VERSION 5.7 ;
  NOWIREEXTENSIONATPIN ON ;
  DIVIDERCHAR "/" ;
  BUSBITCHARS "[]" ;
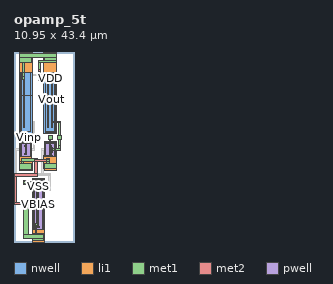
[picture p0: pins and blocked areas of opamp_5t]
MACRO opamp_5t
  CLASS BLOCK ;
  FOREIGN opamp_5t ;
  ORIGIN -1.350 23.320 ;
  SIZE 10.950 BY 43.400 ;
  PIN VDD
    USE POWER ;
    ANTENNADIFFAREA 24.823999 ;
    PORT
      LAYER nwell ;
        RECT 2.510 10.240 5.590 15.940 ;
        RECT 2.500 1.470 5.590 10.240 ;
        RECT 2.500 1.240 5.580 1.470 ;
        RECT 8.060 1.410 11.140 15.880 ;
      LAYER li1 ;
        RECT 2.510 15.470 5.620 20.080 ;
        RECT 2.900 15.380 5.200 15.470 ;
        RECT 8.060 15.400 11.170 20.010 ;
        RECT 2.900 2.030 3.070 15.380 ;
        RECT 3.570 2.935 3.740 14.475 ;
        RECT 5.030 2.030 5.200 15.380 ;
        RECT 2.900 1.860 5.200 2.030 ;
        RECT 8.450 15.320 10.750 15.400 ;
        RECT 8.450 1.970 8.620 15.320 ;
        RECT 9.120 2.875 9.290 14.415 ;
        RECT 10.580 1.970 10.750 15.320 ;
        RECT 8.450 1.800 10.750 1.970 ;
      LAYER met1 ;
        RECT 3.390 19.730 10.720 19.760 ;
        RECT 2.630 19.720 10.720 19.730 ;
        RECT 2.630 18.760 10.980 19.720 ;
        RECT 2.630 17.630 5.390 18.760 ;
        RECT 8.220 18.060 10.980 18.760 ;
        RECT 6.910 17.635 10.980 18.060 ;
        RECT 3.340 14.455 3.650 17.630 ;
        RECT 6.910 15.690 7.335 17.635 ;
        RECT 8.220 17.620 10.980 17.635 ;
        RECT 3.340 13.790 3.770 14.455 ;
        RECT 3.540 2.955 3.770 13.790 ;
        RECT 6.900 14.100 7.340 14.130 ;
        RECT 9.090 14.100 9.320 14.395 ;
        RECT 6.900 13.660 9.320 14.100 ;
        RECT 6.900 13.630 7.340 13.660 ;
        RECT 9.090 2.895 9.320 13.660 ;
      LAYER met2 ;
        RECT 6.910 16.145 7.335 16.170 ;
        RECT 6.880 15.720 7.365 16.145 ;
        RECT 6.910 14.100 7.335 15.720 ;
        RECT 6.870 13.660 7.370 14.100 ;
    END
  END VDD
  PIN Vout
    ANTENNADIFFAREA 3.668500 ;
    PORT
      LAYER li1 ;
        RECT 9.910 2.875 10.080 14.415 ;
        RECT 9.940 -2.850 10.110 -1.660 ;
      LAYER met1 ;
        RECT 9.880 4.250 10.110 14.395 ;
        RECT 9.880 4.240 11.920 4.250 ;
        RECT 9.880 3.890 11.940 4.240 ;
        RECT 9.880 2.895 10.110 3.890 ;
        RECT 11.540 1.040 11.940 3.890 ;
        RECT 11.300 0.040 12.300 1.040 ;
        RECT 11.540 -1.310 11.940 0.040 ;
        RECT 9.910 -2.070 10.140 -1.680 ;
        RECT 11.540 -2.070 11.960 -1.310 ;
        RECT 9.910 -2.430 11.960 -2.070 ;
        RECT 9.910 -2.830 10.140 -2.430 ;
    END
  END Vout
  PIN Vinm
    ANTENNAGATEAREA 0.575000 ;
    PORT
      LAYER li1 ;
        RECT 9.380 -1.490 9.880 -1.320 ;
        RECT 9.380 -3.190 9.880 -3.020 ;
      LAYER met1 ;
        RECT 9.150 0.110 10.150 1.110 ;
        RECT 9.540 -1.290 9.745 0.110 ;
        RECT 9.400 -1.520 9.860 -1.290 ;
        RECT 9.540 -2.990 9.745 -1.520 ;
        RECT 9.400 -3.220 9.860 -2.990 ;
    END
  END Vinm
  PIN Vinp
    ANTENNAGATEAREA 0.575000 ;
    PORT
      LAYER li1 ;
        RECT 3.780 -1.540 4.280 -1.370 ;
        RECT 3.780 -3.240 4.280 -3.070 ;
      LAYER met1 ;
        RECT 3.520 0.040 4.520 1.040 ;
        RECT 3.950 -1.340 4.110 0.040 ;
        RECT 3.800 -1.570 4.260 -1.340 ;
        RECT 3.950 -3.040 4.110 -1.570 ;
        RECT 3.800 -3.270 4.260 -3.040 ;
    END
  END Vinp
  PIN VBIAS
    ANTENNAGATEAREA 4.725000 ;
    PORT
      LAYER li1 ;
        RECT 6.660 -9.940 7.160 -9.770 ;
        RECT 6.660 -19.940 7.160 -19.770 ;
      LAYER met1 ;
        RECT 3.550 -9.585 4.550 -9.260 ;
        RECT 3.550 -9.935 7.205 -9.585 ;
        RECT 3.550 -10.260 4.550 -9.935 ;
        RECT 6.680 -9.970 7.140 -9.935 ;
        RECT 6.820 -19.740 6.990 -9.970 ;
        RECT 6.680 -19.970 7.140 -19.740 ;
    END
  END VBIAS
  PIN VSS
    USE POWER ;
    ANTENNADIFFAREA 16.654699 ;
    PORT
      LAYER pwell ;
        RECT 2.630 -4.170 5.430 -0.440 ;
        RECT 8.230 -4.120 11.030 -0.390 ;
        RECT 5.510 -20.870 8.310 -8.840 ;
      LAYER li1 ;
        RECT 2.870 -0.850 5.190 -0.680 ;
        RECT 2.870 -3.720 3.040 -0.850 ;
        RECT 5.020 -3.720 5.190 -0.850 ;
        RECT 8.470 -0.800 10.790 -0.630 ;
        RECT 8.470 -3.640 8.640 -0.800 ;
        RECT 8.200 -3.710 10.080 -3.640 ;
        RECT 10.620 -3.710 10.790 -0.800 ;
        RECT 2.610 -5.030 5.460 -3.720 ;
        RECT 2.600 -7.020 5.470 -5.030 ;
        RECT 8.200 -6.515 11.110 -3.710 ;
        RECT 8.230 -7.070 11.110 -6.515 ;
        RECT 5.750 -9.250 8.070 -9.080 ;
        RECT 5.750 -20.460 5.920 -9.250 ;
        RECT 6.430 -19.600 6.600 -10.110 ;
        RECT 7.900 -20.460 8.070 -9.250 ;
        RECT 5.750 -20.500 8.070 -20.460 ;
        RECT 5.500 -23.320 8.340 -20.500 ;
      LAYER met1 ;
        RECT 6.110 -4.300 6.650 -4.270 ;
        RECT 3.030 -4.840 6.650 -4.300 ;
        RECT 3.030 -5.320 3.620 -4.840 ;
        RECT 6.110 -4.870 6.650 -4.840 ;
        RECT 8.830 -4.930 9.450 -4.370 ;
        RECT 2.580 -6.760 5.440 -5.320 ;
        RECT 8.860 -5.340 9.420 -4.930 ;
        RECT 8.210 -6.780 11.080 -5.340 ;
        RECT 3.610 -21.620 4.610 -14.000 ;
        RECT 6.400 -19.050 6.630 -10.130 ;
        RECT 6.180 -19.580 6.630 -19.050 ;
        RECT 6.180 -21.380 6.490 -19.580 ;
        RECT 5.630 -21.620 8.140 -21.380 ;
        RECT 3.610 -22.620 8.140 -21.620 ;
        RECT 5.630 -22.920 8.140 -22.620 ;
      LAYER met2 ;
        RECT 6.080 -4.370 6.680 -4.300 ;
        RECT 8.860 -4.370 9.420 -4.340 ;
        RECT 6.000 -4.930 9.420 -4.370 ;
        RECT 6.110 -7.740 6.650 -4.930 ;
        RECT 8.860 -4.960 9.420 -4.930 ;
        RECT 1.350 -8.280 6.650 -7.740 ;
        RECT 1.365 -14.340 1.880 -8.280 ;
        RECT 3.580 -14.340 4.640 -14.030 ;
        RECT 1.365 -14.855 4.640 -14.340 ;
        RECT 3.580 -15.030 4.640 -14.855 ;
    END
  END VSS
  OBS
      LAYER li1 ;
        RECT 3.800 14.690 4.300 14.860 ;
        RECT 9.350 14.630 9.850 14.800 ;
        RECT 4.360 2.935 4.530 14.475 ;
        RECT 3.800 2.550 4.300 2.720 ;
        RECT 9.350 2.490 9.850 2.660 ;
        RECT 3.550 -2.900 3.720 -1.710 ;
        RECT 4.340 -2.900 4.510 -1.710 ;
        RECT 9.150 -2.850 9.320 -1.660 ;
        RECT 7.220 -19.600 7.390 -10.110 ;
      LAYER met1 ;
        RECT 3.820 14.830 4.280 14.890 ;
        RECT 3.820 14.660 9.830 14.830 ;
        RECT 3.940 2.775 4.140 14.660 ;
        RECT 9.370 14.600 9.830 14.660 ;
        RECT 4.330 4.240 4.560 14.455 ;
        RECT 4.330 3.890 6.050 4.240 ;
        RECT 4.330 2.955 4.560 3.890 ;
        RECT 5.700 2.775 6.050 3.890 ;
        RECT 3.895 2.750 6.050 2.775 ;
        RECT 3.820 2.520 6.050 2.750 ;
        RECT 9.510 2.690 9.740 14.600 ;
        RECT 3.895 2.425 6.050 2.520 ;
        RECT 9.370 2.460 9.830 2.690 ;
        RECT 3.520 -2.060 3.750 -1.730 ;
        RECT 1.650 -2.440 3.750 -2.060 ;
        RECT 1.650 -7.810 2.030 -2.440 ;
        RECT 3.520 -2.880 3.750 -2.440 ;
        RECT 4.310 -2.060 4.540 -1.730 ;
        RECT 5.700 -2.060 6.050 2.425 ;
        RECT 9.120 -2.060 9.350 -1.680 ;
        RECT 4.310 -2.405 6.050 -2.060 ;
        RECT 4.310 -2.410 6.010 -2.405 ;
        RECT 4.310 -2.880 4.540 -2.410 ;
        RECT 7.610 -2.490 9.350 -2.060 ;
        RECT 7.625 -7.775 8.030 -2.490 ;
        RECT 9.120 -2.830 9.350 -2.490 ;
        RECT 6.785 -7.810 9.680 -7.775 ;
        RECT 1.650 -8.170 9.680 -7.810 ;
        RECT 1.650 -8.190 7.210 -8.170 ;
        RECT 7.625 -8.180 9.680 -8.170 ;
        RECT 7.190 -11.140 7.420 -10.130 ;
        RECT 9.275 -11.135 9.680 -8.180 ;
        RECT 8.440 -11.140 9.680 -11.135 ;
        RECT 7.190 -11.540 9.680 -11.140 ;
        RECT 7.190 -11.570 8.920 -11.540 ;
        RECT 7.190 -19.580 7.420 -11.570 ;
  END
END opamp_5t
END LIBRARY

